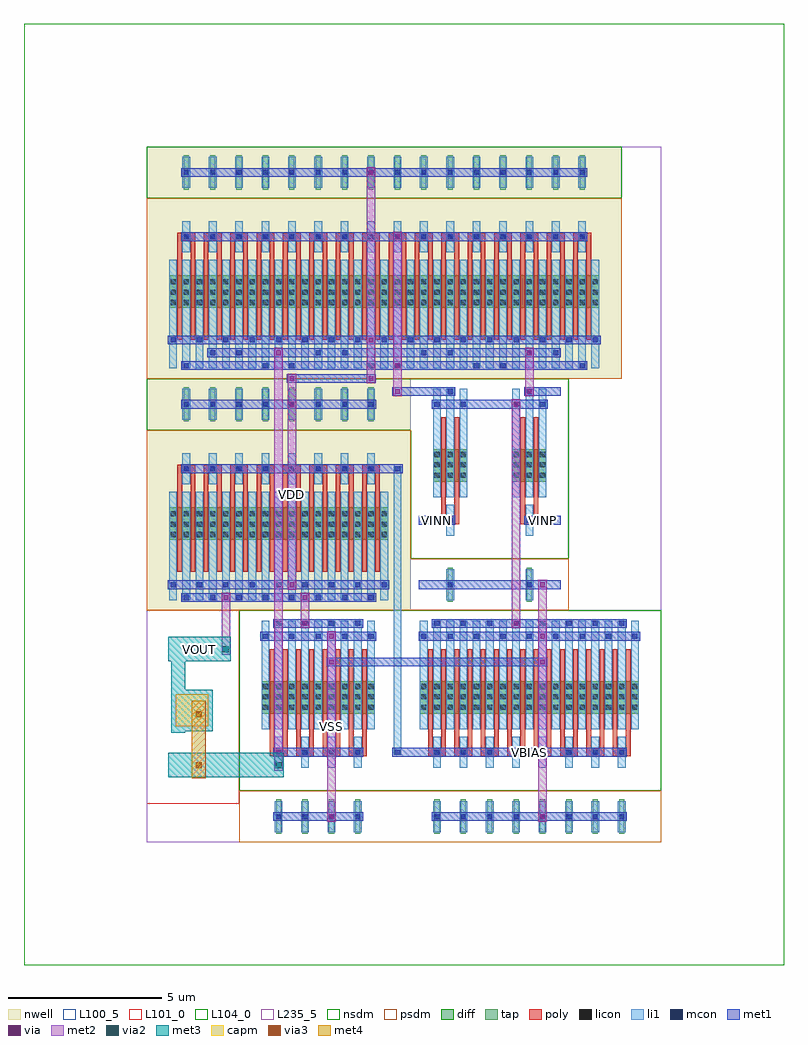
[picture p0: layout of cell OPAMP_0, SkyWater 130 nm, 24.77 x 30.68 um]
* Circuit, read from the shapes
.subckt OPAMP_0 VBIAS VDD VINN VINP VOUT VSS
XM1 VOUT n1 VSS VSS sky130_fd_pr__nfet_01v8 w=1.05 l=0.15 m=8
XM2 n2 VBIAS VSS VSS sky130_fd_pr__nfet_01v8 w=1.05 l=0.15 m=16
XM3 n3 VINN n2 VSS sky130_fd_pr__nfet_01v8 w=1.05 l=0.15 m=2
XM4 n1 VINP n2 VSS sky130_fd_pr__nfet_01v8 w=1.05 l=0.15 m=2
XM5 VOUT VBIAS VDD VDD sky130_fd_pr__pfet_01v8 w=1.05 l=0.15 m=16
XM6 n3 n3 VDD VDD sky130_fd_pr__pfet_01v8 w=1.05 l=0.15 m=16
XM7 n1 n3 VDD VDD sky130_fd_pr__pfet_01v8 w=1.05 l=0.15 m=16
XC8 n1 VOUT sky130_fd_pr__cap_mim_m3_1 w=1.05 l=1.05
.ends

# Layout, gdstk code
from math import pi, radians
import gdstk
lib = gdstk.Library(unit=1e-6, precision=1e-09)
def R(c, l, rs):  # rectangles x0, y0, x1, y1
    for r in rs: c.add(gdstk.rectangle(r[:2], r[2:], *l))
def A(c, l, x, y, w, h, nx, ny, dx, dy):  # array of equal rectangles
    R(c, l, [(x+i*dx, y+j*dy, x+i*dx+w, y+j*dy+h) for i in range(nx) for j in range(ny)])
def P(c, l, *ps):  # polygons
    for p in ps: c.add(gdstk.Polygon(p, *l))
nwell = (64, 20)
diff = (65, 20)
tap = (65, 44)
poly = (66, 20)
licon = (66, 44)
li1 = (67, 20)
mcon = (67, 44)
met1 = (68, 20)
via = (68, 44)
met2 = (69, 20)
via2 = (69, 44)
met3 = (70, 20)
via3 = (70, 44)
met4 = (71, 20)
capm = (89, 44)
nsdm = (93, 44)
psdm = (94, 20)
L100_5 = (100, 5)
L101_0 = (101, 0)
L104_0 = (104, 0)
L235_5 = (235, 5)

scm_pmos_2270758_x8_y1_1 = lib.new_cell('SCM_PMOS_2270758_X8_Y1_1785369801')
R(scm_pmos_2270758_x8_y1_1, nwell, [(0,0,15.48,7.56)])
R(scm_pmos_2270758_x8_y1_1, diff, [(0.735,2.31,14.745,3.36)])
A(scm_pmos_2270758_x8_y1_1, tap, 1.205, 6.16, 0.17, 1.12, 16, 1, 0.86, 0)
A(scm_pmos_2270758_x8_y1_1, poly, 1, 1.26, 0.15, 3.36, 32, 1, 0.43, 0)
A(scm_pmos_2270758_x8_y1_1, poly, 1, 4.485, 0.58, 0.27, 16, 1, 0.86, 0)
A(scm_pmos_2270758_x8_y1_1, licon, 0.775, 2.39, 0.17, 0.17, 3, 3, 0.43, 0.34)
A(scm_pmos_2270758_x8_y1_1, licon, 1.635, 2.39, 0.17, 0.17, 3, 3, 0.43, 0.34)
A(scm_pmos_2270758_x8_y1_1, licon, 2.495, 2.39, 0.17, 0.17, 3, 3, 0.43, 0.34)
A(scm_pmos_2270758_x8_y1_1, licon, 3.355, 2.39, 0.17, 0.17, 3, 3, 0.43, 0.34)
A(scm_pmos_2270758_x8_y1_1, licon, 4.215, 2.39, 0.17, 0.17, 3, 3, 0.43, 0.34)
A(scm_pmos_2270758_x8_y1_1, licon, 5.075, 2.39, 0.17, 0.17, 3, 3, 0.43, 0.34)
A(scm_pmos_2270758_x8_y1_1, licon, 5.935, 2.39, 0.17, 0.17, 3, 3, 0.43, 0.34)
A(scm_pmos_2270758_x8_y1_1, licon, 6.795, 2.39, 0.17, 0.17, 3, 3, 0.43, 0.34)
A(scm_pmos_2270758_x8_y1_1, licon, 7.655, 2.39, 0.17, 0.17, 3, 3, 0.43, 0.34)
A(scm_pmos_2270758_x8_y1_1, licon, 8.515, 2.39, 0.17, 0.17, 3, 3, 0.43, 0.34)
A(scm_pmos_2270758_x8_y1_1, licon, 9.375, 2.39, 0.17, 0.17, 3, 3, 0.43, 0.34)
A(scm_pmos_2270758_x8_y1_1, licon, 10.235, 2.39, 0.17, 0.17, 3, 3, 0.43, 0.34)
A(scm_pmos_2270758_x8_y1_1, licon, 11.095, 2.39, 0.17, 0.17, 3, 3, 0.43, 0.34)
A(scm_pmos_2270758_x8_y1_1, licon, 11.955, 2.39, 0.17, 0.17, 3, 3, 0.43, 0.34)
A(scm_pmos_2270758_x8_y1_1, licon, 12.815, 2.39, 0.17, 0.17, 3, 3, 0.43, 0.34)
A(scm_pmos_2270758_x8_y1_1, licon, 13.675, 2.39, 0.17, 0.17, 3, 3, 0.43, 0.34)
A(scm_pmos_2270758_x8_y1_1, licon, 1.205, 4.535, 0.17, 0.17, 16, 2, 0.86, 2.1)
A(scm_pmos_2270758_x8_y1_1, li1, 0.735, 0.335, 0.25, 3.53, 33, 1, 0.43, 0)
A(scm_pmos_2270758_x8_y1_1, li1, 1.165, 4.115, 0.25, 1.01, 16, 2, 0.86, 2.1)
A(scm_pmos_2270758_x8_y1_1, mcon, 0.775, 1.175, 0.17, 0.17, 17, 1, 0.86, 0)
A(scm_pmos_2270758_x8_y1_1, mcon, 1.205, 4.535, 0.17, 0.17, 16, 2, 0.86, 2.1)
R(scm_pmos_2270758_x8_y1_1, mcon, [(1.205,0.335,1.375,0.505), (3.785,0.335,3.955,0.505), (4.645,0.335,4.815,0.505), (7.225,0.335,7.395,0.505), (8.085,0.335,8.255,0.505), (10.665,0.335,10.835,0.505), (11.525,0.335,11.695,0.505), (14.105,0.335,14.275,0.505), (2.065,0.755,2.235,0.925), (2.925,0.755,3.095,0.925), (5.505,0.755,5.675,0.925), (6.365,0.755,6.535,0.925), (8.945,0.755,9.115,0.925), (9.805,0.755,9.975,0.925), (12.385,0.755,12.555,0.925), (13.245,0.755,13.415,0.925)])
R(scm_pmos_2270758_x8_y1_1, met1, [(1.12,0.28,14.36,0.56), (1.98,0.7,13.5,0.98), (0.69,1.12,14.79,1.4), (1.12,4.48,14.36,4.76), (1.12,6.58,14.36,6.86)])
R(scm_pmos_2270758_x8_y1_1, via, [(7.235,0.345,7.385,0.495), (8.095,1.185,8.245,1.335), (7.235,4.545,7.385,4.695), (8.095,6.645,8.245,6.795)])
R(scm_pmos_2270758_x8_y1_1, met2, [(7.17,0.26,7.45,4.78), (8.03,1.1,8.31,6.88)])
R(scm_pmos_2270758_x8_y1_1, nsdm, [(0,5.88,15.48,7.56)])
R(scm_pmos_2270758_x8_y1_1, psdm, [(0,0,15.48,5.88)])
R(scm_pmos_2270758_x8_y1_1, L100_5, [(0,0,15.48,7.56)])

cap_2t_96113034_17853697 = lib.new_cell('CAP_2T_96113034_1785369796')
R(cap_2t_96113034_17853697, met3, [(0.265,0.86,2.315,1.66), (1.76,2.32,2.21,4.84), (0.86,2.37,2.21,3.72), (0.265,4.64,2.315,5.44)])
R(cap_2t_96113034_17853697, via3, [(1.21,1.16,1.41,1.36), (1.21,2.82,1.41,3.02)])
R(cap_2t_96113034_17853697, met4, [(1.085,0.83,1.535,3.35)])
R(cap_2t_96113034_17853697, capm, [(1.01,2.52,2.06,3.57)])
R(cap_2t_96113034_17853697, L100_5, [(0,0,3.01,6.3)])
R(cap_2t_96113034_17853697, L101_0, [(0,0,3.01,6.3)])

nmos_s_72323505_x8_y1_17 = lib.new_cell('NMOS_S_72323505_X8_Y1_1785369798')
R(nmos_s_72323505_x8_y1_17, diff, [(0.735,2.31,7.865,3.36)])
A(nmos_s_72323505_x8_y1_17, tap, 1.205, 6.16, 0.17, 1.12, 8, 1, 0.86, 0)
A(nmos_s_72323505_x8_y1_17, poly, 1, 1.26, 0.15, 3.36, 16, 1, 0.43, 0)
A(nmos_s_72323505_x8_y1_17, poly, 1, 4.485, 0.58, 0.27, 8, 1, 0.86, 0)
A(nmos_s_72323505_x8_y1_17, licon, 0.775, 2.39, 0.17, 0.17, 3, 3, 0.43, 0.34)
A(nmos_s_72323505_x8_y1_17, licon, 1.635, 2.39, 0.17, 0.17, 3, 3, 0.43, 0.34)
A(nmos_s_72323505_x8_y1_17, licon, 2.495, 2.39, 0.17, 0.17, 3, 3, 0.43, 0.34)
A(nmos_s_72323505_x8_y1_17, licon, 3.355, 2.39, 0.17, 0.17, 3, 3, 0.43, 0.34)
A(nmos_s_72323505_x8_y1_17, licon, 4.215, 2.39, 0.17, 0.17, 3, 3, 0.43, 0.34)
A(nmos_s_72323505_x8_y1_17, licon, 5.075, 2.39, 0.17, 0.17, 3, 3, 0.43, 0.34)
A(nmos_s_72323505_x8_y1_17, licon, 5.935, 2.39, 0.17, 0.17, 3, 3, 0.43, 0.34)
A(nmos_s_72323505_x8_y1_17, licon, 6.795, 2.39, 0.17, 0.17, 3, 3, 0.43, 0.34)
A(nmos_s_72323505_x8_y1_17, licon, 1.205, 4.535, 0.17, 0.17, 8, 2, 0.86, 2.1)
A(nmos_s_72323505_x8_y1_17, li1, 0.735, 0.335, 0.25, 3.53, 17, 1, 0.43, 0)
A(nmos_s_72323505_x8_y1_17, li1, 1.165, 4.115, 0.25, 1.01, 8, 2, 0.86, 2.1)
A(nmos_s_72323505_x8_y1_17, mcon, 1.205, 0.335, 0.17, 0.17, 8, 2, 0.86, 4.2)
A(nmos_s_72323505_x8_y1_17, mcon, 0.775, 0.755, 0.17, 0.17, 9, 1, 0.86, 0)
A(nmos_s_72323505_x8_y1_17, mcon, 1.205, 6.635, 0.17, 0.17, 8, 1, 0.86, 0)
R(nmos_s_72323505_x8_y1_17, met1, [(1.12,0.28,7.48,0.56), (0.69,0.7,7.91,0.98), (1.12,4.48,7.48,4.76), (1.12,6.58,7.48,6.86)])
R(nmos_s_72323505_x8_y1_17, via, [(4.655,0.765,4.805,0.915), (4.655,6.645,4.805,6.795)])
R(nmos_s_72323505_x8_y1_17, met2, [(4.59,0.68,4.87,6.88)])
R(nmos_s_72323505_x8_y1_17, nsdm, [(0,0,8.6,5.88)])
R(nmos_s_72323505_x8_y1_17, psdm, [(0,5.88,8.6,7.56)])
R(nmos_s_72323505_x8_y1_17, L100_5, [(0,0,8.6,7.56)])

nmos_s_98719586_x4_y1_17 = lib.new_cell('NMOS_S_98719586_X4_Y1_1785369799')
R(nmos_s_98719586_x4_y1_17, diff, [(0.735,2.31,4.425,3.36)])
A(nmos_s_98719586_x4_y1_17, tap, 1.205, 6.16, 0.17, 1.12, 4, 1, 0.86, 0)
A(nmos_s_98719586_x4_y1_17, poly, 1, 1.26, 0.15, 3.36, 8, 1, 0.43, 0)
A(nmos_s_98719586_x4_y1_17, poly, 1, 4.485, 0.58, 0.27, 4, 1, 0.86, 0)
A(nmos_s_98719586_x4_y1_17, licon, 0.775, 2.39, 0.17, 0.17, 3, 3, 0.43, 0.34)
A(nmos_s_98719586_x4_y1_17, licon, 1.635, 2.39, 0.17, 0.17, 3, 3, 0.43, 0.34)
A(nmos_s_98719586_x4_y1_17, licon, 2.495, 2.39, 0.17, 0.17, 3, 3, 0.43, 0.34)
A(nmos_s_98719586_x4_y1_17, licon, 3.355, 2.39, 0.17, 0.17, 3, 3, 0.43, 0.34)
A(nmos_s_98719586_x4_y1_17, licon, 1.205, 4.535, 0.17, 0.17, 4, 2, 0.86, 2.1)
A(nmos_s_98719586_x4_y1_17, li1, 0.735, 0.335, 0.25, 3.53, 9, 1, 0.43, 0)
A(nmos_s_98719586_x4_y1_17, li1, 1.165, 4.115, 0.25, 1.01, 4, 2, 0.86, 2.1)
A(nmos_s_98719586_x4_y1_17, mcon, 1.205, 0.335, 0.17, 0.17, 4, 2, 0.86, 4.2)
A(nmos_s_98719586_x4_y1_17, mcon, 0.775, 0.755, 0.17, 0.17, 5, 1, 0.86, 0)
A(nmos_s_98719586_x4_y1_17, mcon, 1.205, 6.635, 0.17, 0.17, 4, 1, 0.86, 0)
R(nmos_s_98719586_x4_y1_17, met1, [(1.12,0.28,4.04,0.56), (0.69,0.7,4.47,0.98), (1.12,4.48,4.04,4.76), (1.12,6.58,4.04,6.86)])
R(nmos_s_98719586_x4_y1_17, via, [(2.935,0.765,3.085,0.915), (2.935,6.645,3.085,6.795)])
R(nmos_s_98719586_x4_y1_17, met2, [(2.87,0.68,3.15,6.88)])
R(nmos_s_98719586_x4_y1_17, nsdm, [(0,0,5.16,5.88)])
R(nmos_s_98719586_x4_y1_17, psdm, [(0,5.88,5.16,7.56)])
R(nmos_s_98719586_x4_y1_17, L100_5, [(0,0,5.16,7.56)])

pmos_s_62671986_x8_y1_17 = lib.new_cell('PMOS_S_62671986_X8_Y1_1785369800')
R(pmos_s_62671986_x8_y1_17, nwell, [(0,0,8.6,7.56)])
R(pmos_s_62671986_x8_y1_17, diff, [(0.735,2.31,7.865,3.36)])
A(pmos_s_62671986_x8_y1_17, tap, 1.205, 6.16, 0.17, 1.12, 8, 1, 0.86, 0)
A(pmos_s_62671986_x8_y1_17, poly, 1, 1.26, 0.15, 3.36, 16, 1, 0.43, 0)
A(pmos_s_62671986_x8_y1_17, poly, 1, 4.485, 0.58, 0.27, 8, 1, 0.86, 0)
A(pmos_s_62671986_x8_y1_17, licon, 0.775, 2.39, 0.17, 0.17, 3, 3, 0.43, 0.34)
A(pmos_s_62671986_x8_y1_17, licon, 1.635, 2.39, 0.17, 0.17, 3, 3, 0.43, 0.34)
A(pmos_s_62671986_x8_y1_17, licon, 2.495, 2.39, 0.17, 0.17, 3, 3, 0.43, 0.34)
A(pmos_s_62671986_x8_y1_17, licon, 3.355, 2.39, 0.17, 0.17, 3, 3, 0.43, 0.34)
A(pmos_s_62671986_x8_y1_17, licon, 4.215, 2.39, 0.17, 0.17, 3, 3, 0.43, 0.34)
A(pmos_s_62671986_x8_y1_17, licon, 5.075, 2.39, 0.17, 0.17, 3, 3, 0.43, 0.34)
A(pmos_s_62671986_x8_y1_17, licon, 5.935, 2.39, 0.17, 0.17, 3, 3, 0.43, 0.34)
A(pmos_s_62671986_x8_y1_17, licon, 6.795, 2.39, 0.17, 0.17, 3, 3, 0.43, 0.34)
A(pmos_s_62671986_x8_y1_17, licon, 1.205, 4.535, 0.17, 0.17, 8, 2, 0.86, 2.1)
A(pmos_s_62671986_x8_y1_17, li1, 0.735, 0.335, 0.25, 3.53, 17, 1, 0.43, 0)
A(pmos_s_62671986_x8_y1_17, li1, 1.165, 4.115, 0.25, 1.01, 8, 2, 0.86, 2.1)
A(pmos_s_62671986_x8_y1_17, mcon, 1.205, 0.335, 0.17, 0.17, 8, 2, 0.86, 4.2)
A(pmos_s_62671986_x8_y1_17, mcon, 0.775, 0.755, 0.17, 0.17, 9, 1, 0.86, 0)
A(pmos_s_62671986_x8_y1_17, mcon, 1.205, 6.635, 0.17, 0.17, 8, 1, 0.86, 0)
R(pmos_s_62671986_x8_y1_17, met1, [(1.12,0.28,7.48,0.56), (0.69,0.7,7.91,0.98), (1.12,4.48,7.48,4.76), (1.12,6.58,7.48,6.86)])
R(pmos_s_62671986_x8_y1_17, via, [(4.655,0.765,4.805,0.915), (4.655,6.645,4.805,6.795)])
R(pmos_s_62671986_x8_y1_17, met2, [(4.59,0.68,4.87,6.88)])
R(pmos_s_62671986_x8_y1_17, nsdm, [(0,5.88,8.6,7.56)])
R(pmos_s_62671986_x8_y1_17, psdm, [(0,0,8.6,5.88)])
R(pmos_s_62671986_x8_y1_17, L100_5, [(0,0,8.6,7.56)])

nmos_4t_95495835_x1_y1_1 = lib.new_cell('NMOS_4T_95495835_X1_Y1_1785369797')
R(nmos_4t_95495835_x1_y1_1, diff, [(0.735,2.31,1.845,3.36)])
R(nmos_4t_95495835_x1_y1_1, tap, [(1.205,6.16,1.375,7.28)])
R(nmos_4t_95495835_x1_y1_1, poly, [(1,1.26,1.15,4.62), (1.43,1.26,1.58,4.62), (1,4.485,1.58,4.755)])
A(nmos_4t_95495835_x1_y1_1, licon, 0.775, 2.39, 0.17, 0.17, 3, 3, 0.43, 0.34)
R(nmos_4t_95495835_x1_y1_1, licon, [(1.205,4.535,1.375,4.705), (1.205,6.635,1.375,6.805)])
A(nmos_4t_95495835_x1_y1_1, li1, 0.735, 0.335, 0.25, 3.53, 3, 1, 0.43, 0)
R(nmos_4t_95495835_x1_y1_1, li1, [(1.165,4.115,1.415,5.125), (1.165,6.215,1.415,7.225)])
R(nmos_4t_95495835_x1_y1_1, mcon, [(1.205,0.335,1.375,0.505), (0.775,0.755,0.945,0.925), (1.635,0.755,1.805,0.925), (1.205,4.535,1.375,4.705), (1.205,6.635,1.375,6.805)])
R(nmos_4t_95495835_x1_y1_1, met1, [(0.26,0.28,1.46,0.56), (0.69,0.7,1.89,0.98), (0.26,4.48,1.46,4.76), (0.26,6.58,1.46,6.86)])
R(nmos_4t_95495835_x1_y1_1, nsdm, [(0,0,2.58,5.88)])
R(nmos_4t_95495835_x1_y1_1, psdm, [(0,5.88,2.58,7.56)])
R(nmos_4t_95495835_x1_y1_1, L100_5, [(0,0,2.58,7.56)])

opamp_0 = lib.new_cell('OPAMP_0')
R(opamp_0, li1, [(8.045,2.855,8.295,3.025), (8.045,2.855,8.295,3.025), (8.045,2.94,8.295,12.18), (8.045,12.095,8.295,12.265), (8.045,12.095,8.295,12.265)])
R(opamp_0, mcon, [(8.085,2.855,8.255,3.025), (8.085,2.855,8.255,3.025), (8.085,12.095,8.255,12.265), (8.085,12.095,8.255,12.265)])
R(opamp_0, met1, [(4.14,2.8,4.46,3.08), (4.14,2.8,4.46,3.08), (4.14,2.8,4.46,3.08), (4.14,2.8,4.46,3.08), (4.14,2.8,4.46,3.08), (4.14,2.8,4.46,3.08), (8,2.8,8.34,3.08), (8,2.8,8.34,3.08), (8.17,2.8,9.46,3.08), (5.86,5.74,6.18,6.02), (5.86,5.74,6.18,6.02), (5.86,5.74,6.18,6.02), (5.86,5.74,6.18,6.02), (5.86,5.74,6.18,6.02), (5.86,5.74,6.18,6.02), (6.02,5.74,12.9,6.02), (12.74,5.74,13.06,6.02), (12.74,5.74,13.06,6.02), (12.74,5.74,13.06,6.02), (12.74,5.74,13.06,6.02), (12.74,5.74,13.06,6.02), (12.74,5.74,13.06,6.02), (5,7,5.32,7.28), (5,7,5.32,7.28), (11.88,7,12.2,7.28), (11.88,7,12.2,7.28), (11.88,7,12.2,7.28), (11.88,7,12.2,7.28), (2.42,7.84,2.74,8.12), (2.42,7.84,2.74,8.12), (2.42,7.84,2.74,8.12), (2.42,7.84,2.74,8.12), (5,7.84,5.32,8.12), (5,7.84,5.32,8.12), (9.89,8.26,12.47,8.54), (12.74,8.26,13.06,8.54), (12.74,8.26,13.06,8.54), (12.74,8.26,13.06,8.54), (12.74,8.26,13.06,8.54), (7.31,12.04,8.17,12.32), (8,12.04,8.34,12.32), (8,12.04,8.34,12.32), (10.32,14.14,12.04,14.42), (11.88,14.14,12.2,14.42), (11.88,14.14,12.2,14.42), (11.88,14.14,12.2,14.42), (11.88,14.14,12.2,14.42), (8.01,14.56,8.33,14.84), (8.01,14.56,8.33,14.84), (8.17,14.56,9.03,14.84), (12.31,14.56,12.63,14.84), (12.31,14.56,12.63,14.84), (4.57,14.98,4.89,15.26), (4.57,14.98,4.89,15.26), (4.73,14.98,7.31,15.26), (7.15,14.98,7.47,15.26), (7.15,14.98,7.47,15.26), (4.14,15.82,4.46,16.1), (4.14,15.82,4.46,16.1), (4.14,15.82,4.46,16.1), (4.14,15.82,4.46,16.1), (12.31,15.82,12.63,16.1), (12.31,15.82,12.63,16.1)])
P(opamp_0, met1, [(0,0),(0,0),(0,0),(0,0)],
  [(0,0),(0,0),(0,0),(0,0)],
  [(0,0),(0,0),(0,0),(0,0)],
  [(0,0),(0,0),(0,0),(0,0)],
  [(0,0),(0,0),(0,0),(0,0)],
  [(0,0),(0,0),(0,0),(0,0)],
  [(0,0),(0,0),(0,0),(0,0)],
  [(0,0),(0,0),(0,0),(0,0)],
  [(0,0),(0,0),(0,0),(0,0)],
  [(0,0),(0,0),(0,0),(0,0)],
  [(0,0),(0,0),(0,0),(0,0)],
  [(0,0),(0,0),(0,0),(0,0)],
  [(0,0),(0,0),(0,0),(0,0)],
  [(0,0),(0,0),(0,0),(0,0)],
  [(0,0),(0,0),(0,0),(0,0)],
  [(0,0),(0,0),(0,0),(0,0)],
  [(0,0),(0,0),(0,0),(0,0)],
  [(0,0),(0,0),(0,0),(0,0)])
R(opamp_0, via, [(4.225,2.865,4.375,3.015), (4.225,2.865,4.375,3.015), (4.225,2.865,4.375,3.015), (4.225,2.865,4.375,3.015), (4.225,2.865,4.375,3.015), (4.225,2.865,4.375,3.015), (5.945,5.805,6.095,5.955), (5.945,5.805,6.095,5.955), (5.945,5.805,6.095,5.955), (5.945,5.805,6.095,5.955), (5.945,5.805,6.095,5.955), (5.945,5.805,6.095,5.955), (12.825,5.805,12.975,5.955), (12.825,5.805,12.975,5.955), (12.825,5.805,12.975,5.955), (12.825,5.805,12.975,5.955), (12.825,5.805,12.975,5.955), (12.825,5.805,12.975,5.955), (5.085,7.065,5.235,7.215), (5.085,7.065,5.235,7.215), (11.965,7.065,12.115,7.215), (11.965,7.065,12.115,7.215), (11.965,7.065,12.115,7.215), (11.965,7.065,12.115,7.215), (2.505,7.905,2.655,8.055), (2.505,7.905,2.655,8.055), (2.505,7.905,2.655,8.055), (2.505,7.905,2.655,8.055), (5.085,7.905,5.235,8.055), (5.085,7.905,5.235,8.055), (12.825,8.325,12.975,8.475), (12.825,8.325,12.975,8.475), (12.825,8.325,12.975,8.475), (12.825,8.325,12.975,8.475), (11.965,14.205,12.115,14.355), (11.965,14.205,12.115,14.355), (11.965,14.205,12.115,14.355), (11.965,14.205,12.115,14.355), (8.095,14.625,8.245,14.775), (8.095,14.625,8.245,14.775), (12.395,14.625,12.545,14.775), (12.395,14.625,12.545,14.775), (4.655,15.045,4.805,15.195), (4.655,15.045,4.805,15.195), (7.235,15.045,7.385,15.195), (7.235,15.045,7.385,15.195), (4.225,15.885,4.375,16.035), (4.225,15.885,4.375,16.035), (4.225,15.885,4.375,16.035), (4.225,15.885,4.375,16.035), (12.395,15.885,12.545,16.035), (12.395,15.885,12.545,16.035)])
R(opamp_0, met2, [(4.16,2.335,4.44,2.705), (4.16,2.335,4.44,2.705), (4.16,2.335,4.44,2.705), (4.16,2.335,4.44,2.705), (4.16,2.335,4.44,2.705), (4.16,2.335,4.44,2.705), (4.16,2.52,4.44,2.94), (4.16,2.78,4.44,3.1), (4.16,2.78,4.44,3.1), (4.16,2.78,4.44,3.1), (4.16,2.78,4.44,3.1), (4.16,2.78,4.44,3.1), (4.16,2.78,4.44,3.1), (4.16,2.94,4.44,15.96), (5.88,5.72,6.16,6.04), (5.88,5.72,6.16,6.04), (5.88,5.72,6.16,6.04), (5.88,5.72,6.16,6.04), (5.88,5.72,6.16,6.04), (5.88,5.72,6.16,6.04), (12.76,5.72,13.04,6.04), (12.76,5.72,13.04,6.04), (12.76,5.72,13.04,6.04), (12.76,5.72,13.04,6.04), (12.76,5.72,13.04,6.04), (12.76,5.72,13.04,6.04), (2.44,6.115,2.72,6.485), (2.44,6.115,2.72,6.485), (2.44,6.115,2.72,6.485), (2.44,6.115,2.72,6.485), (2.44,6.3,2.72,7.98), (12.76,6.72,13.04,8.4), (5.02,6.98,5.3,7.3), (5.02,6.98,5.3,7.3), (11.9,6.98,12.18,7.3), (11.9,6.98,12.18,7.3), (11.9,6.98,12.18,7.3), (11.9,6.98,12.18,7.3), (5.02,7.14,5.3,7.98), (11.9,7.14,12.18,14.28), (2.44,7.82,2.72,8.14), (2.44,7.82,2.72,8.14), (2.44,7.82,2.72,8.14), (2.44,7.82,2.72,8.14), (5.02,7.82,5.3,8.14), (5.02,7.82,5.3,8.14), (12.76,8.24,13.04,8.56), (12.76,8.24,13.04,8.56), (12.76,8.24,13.04,8.56), (12.76,8.24,13.04,8.56), (11.9,14.12,12.18,14.44), (11.9,14.12,12.18,14.44), (11.9,14.12,12.18,14.44), (11.9,14.12,12.18,14.44), (4.59,14.28,4.87,15.12), (8.03,14.54,8.31,14.86), (8.03,14.54,8.31,14.86), (12.33,14.54,12.61,14.86), (12.33,14.54,12.61,14.86), (8.03,14.7,8.31,15.54), (12.33,14.7,12.61,15.96), (4.59,14.96,4.87,15.28), (4.59,14.96,4.87,15.28), (7.17,14.96,7.45,15.28), (7.17,14.96,7.45,15.28), (7.17,15.12,7.45,16.38), (4.16,15.8,4.44,16.12), (4.16,15.8,4.44,16.12), (4.16,15.8,4.44,16.12), (4.16,15.8,4.44,16.12), (12.33,15.8,12.61,16.12), (12.33,15.8,12.61,16.12)])
P(opamp_0, met2, [(0,0),(0,0),(0,0),(0,0)],
  [(0,0),(0,0),(0,0),(0,0)],
  [(0,0),(0,0),(0,0),(0,0)],
  [(0,0),(0,0),(0,0),(0,0)],
  [(0,0),(0,0),(0,0),(0,0)],
  [(0,0),(0,0),(0,0),(0,0)],
  [(0,0),(0,0),(0,0),(0,0)])
R(opamp_0, via2, [(4.2,2.42,4.4,2.62), (4.2,2.42,4.4,2.62), (4.2,2.42,4.4,2.62), (4.2,2.42,4.4,2.62), (4.2,2.42,4.4,2.62), (4.2,2.42,4.4,2.62), (2.48,6.2,2.68,6.4), (2.48,6.2,2.68,6.4), (2.48,6.2,2.68,6.4), (2.48,6.2,2.68,6.4)])
R(opamp_0, met3, [(2.58,2.12,4.3,2.92), (4.135,2.12,4.465,2.92), (4.135,2.12,4.465,2.92), (4.135,2.12,4.465,2.92), (4.135,2.12,4.465,2.92), (4.135,2.12,4.465,2.92), (4.135,2.12,4.465,2.92), (2.415,5.9,2.745,6.7), (2.415,5.9,2.745,6.7), (2.415,5.9,2.745,6.7), (2.415,5.9,2.745,6.7)])
P(opamp_0, met3, [(0,0),(0,0),(0,0),(0,0)],
  [(0,0),(0,0),(0,0),(0,0)],
  [(0,0),(0,0),(0,0),(0,0)])
R(opamp_0, L104_0, [(-4,-4,20.77,26.68)])
R(opamp_0, L235_5, [(0,0,16.77,22.68)])
opamp_0.add(gdstk.Reference(scm_pmos_2270758_x8_y1_1, (15.48,15.12), rotation=pi, x_reflection=True))
opamp_0.add(gdstk.Reference(cap_2t_96113034_17853697, (3.01,1.26), rotation=pi, x_reflection=True))
opamp_0.add(gdstk.Reference(nmos_s_72323505_x8_y1_17, (8.17,7.56), x_reflection=True))
opamp_0.add(gdstk.Reference(nmos_s_98719586_x4_y1_17, (3.01,7.56), x_reflection=True))
opamp_0.add(gdstk.Reference(pmos_s_62671986_x8_y1_17, (0,7.56)))
opamp_0.add(gdstk.Reference(nmos_4t_95495835_x1_y1_1, (8.6,15.12), x_reflection=True))
opamp_0.add(gdstk.Reference(nmos_4t_95495835_x1_y1_1, (13.76,15.12), rotation=pi))
opamp_0.add(gdstk.Label('VDD', (4.73,11.34), layer=69, texttype=5))
opamp_0.add(gdstk.Label('VOUT', (1.72,6.3), layer=70, texttype=5))
opamp_0.add(gdstk.Label('VBIAS', (12.47,2.94), layer=68, texttype=5))
opamp_0.add(gdstk.Label('VSS', (6.02,3.78), layer=69, texttype=5))
opamp_0.add(gdstk.Label('VINN', (9.46,10.5), layer=68, texttype=5))
opamp_0.add(gdstk.Label('VINP', (12.9,10.5), layer=68, texttype=5))

lib.write_gds('OPAMP_0.gds')
